VERSION 5.8 ;
BUSBITCHARS "[]" ;
DIVIDERCHAR "/" ;
UNITS
    DATABASE MICRONS 1000 ;
END UNITS

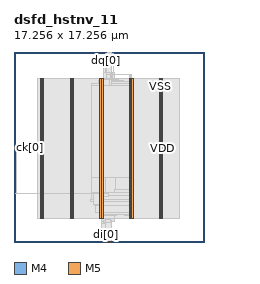
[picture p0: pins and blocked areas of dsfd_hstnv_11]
MACRO dsfd_hstnv_11
  FOREIGN dsfd_hstnv_11 0 0 ;
  CLASS BLOCK ;
  SIZE 17.256 BY 17.256 ;
  PIN ck[0]
    DIRECTION INPUT ;
    USE SIGNAL ;
    PORT
      LAYER M4 ;
        RECT  0 8.592 0.084 8.616 ;
    END
    PORT
      LAYER M4 ;
        RECT  0.06 8.592 0.227 8.616 ;
    END
  END ck[0]
  PIN di[0]
    DIRECTION INPUT ;
    USE SIGNAL ;
    PORT
      LAYER M5 ;
        RECT  8.352 0 8.376 0.084 ;
    END
  END di[0]
  PIN di[10]
    DIRECTION INPUT ;
    USE SIGNAL ;
    PORT
      LAYER M5 ;
        RECT  8.832 0 8.856 0.084 ;
    END
  END di[10]
  PIN di[1]
    DIRECTION INPUT ;
    USE SIGNAL ;
    PORT
      LAYER M5 ;
        RECT  8.4 0 8.424 0.084 ;
    END
  END di[1]
  PIN di[2]
    DIRECTION INPUT ;
    USE SIGNAL ;
    PORT
      LAYER M5 ;
        RECT  8.448 0 8.472 0.084 ;
    END
  END di[2]
  PIN di[3]
    DIRECTION INPUT ;
    USE SIGNAL ;
    PORT
      LAYER M5 ;
        RECT  8.496 0 8.52 0.084 ;
    END
  END di[3]
  PIN di[4]
    DIRECTION INPUT ;
    USE SIGNAL ;
    PORT
      LAYER M5 ;
        RECT  8.544 0 8.568 0.084 ;
    END
  END di[4]
  PIN di[5]
    DIRECTION INPUT ;
    USE SIGNAL ;
    PORT
      LAYER M5 ;
        RECT  8.592 0 8.616 0.084 ;
    END
  END di[5]
  PIN di[6]
    DIRECTION INPUT ;
    USE SIGNAL ;
    PORT
      LAYER M5 ;
        RECT  8.64 0 8.664 0.084 ;
    END
  END di[6]
  PIN di[7]
    DIRECTION INPUT ;
    USE SIGNAL ;
    PORT
      LAYER M5 ;
        RECT  8.688 0 8.712 0.084 ;
    END
  END di[7]
  PIN di[8]
    DIRECTION INPUT ;
    USE SIGNAL ;
    PORT
      LAYER M5 ;
        RECT  8.736 0 8.76 0.084 ;
    END
  END di[8]
  PIN di[9]
    DIRECTION INPUT ;
    USE SIGNAL ;
    PORT
      LAYER M5 ;
        RECT  8.784 0 8.808 0.084 ;
    END
  END di[9]
  PIN dq[0]
    DIRECTION OUTPUT ;
    USE SIGNAL ;
    PORT
      LAYER M5 ;
        RECT  8.352 17.172 8.376 17.256 ;
    END
  END dq[0]
  PIN dq[10]
    DIRECTION OUTPUT ;
    USE SIGNAL ;
    PORT
      LAYER M5 ;
        RECT  8.832 17.172 8.856 17.256 ;
    END
  END dq[10]
  PIN dq[1]
    DIRECTION OUTPUT ;
    USE SIGNAL ;
    PORT
      LAYER M5 ;
        RECT  8.4 17.172 8.424 17.256 ;
    END
  END dq[1]
  PIN dq[2]
    DIRECTION OUTPUT ;
    USE SIGNAL ;
    PORT
      LAYER M5 ;
        RECT  8.448 17.172 8.472 17.256 ;
    END
  END dq[2]
  PIN dq[3]
    DIRECTION OUTPUT ;
    USE SIGNAL ;
    PORT
      LAYER M5 ;
        RECT  8.496 17.172 8.52 17.256 ;
    END
  END dq[3]
  PIN dq[4]
    DIRECTION OUTPUT ;
    USE SIGNAL ;
    PORT
      LAYER M5 ;
        RECT  8.544 17.172 8.568 17.256 ;
    END
  END dq[4]
  PIN dq[5]
    DIRECTION OUTPUT ;
    USE SIGNAL ;
    PORT
      LAYER M5 ;
        RECT  8.592 17.172 8.616 17.256 ;
    END
  END dq[5]
  PIN dq[6]
    DIRECTION OUTPUT ;
    USE SIGNAL ;
    PORT
      LAYER M5 ;
        RECT  8.64 17.172 8.664 17.256 ;
    END
  END dq[6]
  PIN dq[7]
    DIRECTION OUTPUT ;
    USE SIGNAL ;
    PORT
      LAYER M5 ;
        RECT  8.688 17.172 8.712 17.256 ;
    END
  END dq[7]
  PIN dq[8]
    DIRECTION OUTPUT ;
    USE SIGNAL ;
    PORT
      LAYER M5 ;
        RECT  8.736 17.172 8.76 17.256 ;
    END
  END dq[8]
  PIN dq[9]
    DIRECTION OUTPUT ;
    USE SIGNAL ;
    PORT
      LAYER M5 ;
        RECT  8.784 17.172 8.808 17.256 ;
    END
  END dq[9]
  PIN VDD
    DIRECTION INOUT ;
    USE POWER ;
    PORT
      LAYER M5 ;
        RECT  13.392 2.151 13.512 14.873 ;
        RECT  10.692 2.151 10.812 14.873 ;
        RECT  7.992 2.151 8.112 14.873 ;
        RECT  5.292 2.151 5.412 14.873 ;
        RECT  2.592 2.151 2.712 14.873 ;
    END
  END VDD
  PIN VSS
    DIRECTION INOUT ;
    USE GROUND ;
    PORT
      LAYER M5 ;
        RECT  13.2 2.137 13.32 14.859 ;
        RECT  10.5 2.137 10.62 14.859 ;
        RECT  7.8 2.137 7.92 14.859 ;
        RECT  5.1 2.137 5.22 14.859 ;
        RECT  2.4 2.137 2.52 14.859 ;
    END
  END VSS
  # OT_OBS_CLOSED layer=M5 d_um=1.536 added=0
  OBS
    LAYER RVTN ;
     RECT  2.16 2.16 15.066 2.295 ;
     RECT  2.16 2.565 15.066 2.835 ;
     RECT  2.16 3.105 15.066 3.375 ;
     RECT  2.16 3.645 15.066 3.915 ;
     RECT  2.16 4.185 15.066 4.455 ;
     RECT  2.16 4.725 15.066 4.995 ;
     RECT  2.16 5.265 15.066 5.535 ;
     RECT  2.16 5.805 15.066 6.075 ;
     RECT  2.16 6.345 15.066 6.615 ;
     RECT  2.16 6.885 15.066 7.155 ;
     RECT  2.16 7.425 15.066 7.695 ;
     RECT  2.16 7.965 15.066 8.235 ;
     RECT  2.16 8.505 15.066 8.775 ;
     RECT  2.16 9.045 15.066 9.315 ;
     RECT  2.16 9.585 15.066 9.855 ;
     RECT  2.16 10.125 15.066 10.395 ;
     RECT  2.16 10.665 15.066 10.935 ;
     RECT  2.16 11.205 15.066 11.475 ;
     RECT  2.16 11.745 15.066 12.015 ;
     RECT  2.16 12.285 15.066 12.555 ;
     RECT  2.16 12.825 15.066 13.095 ;
     RECT  2.16 13.365 15.066 13.635 ;
     RECT  2.16 13.905 15.066 14.175 ;
     RECT  2.16 14.445 15.066 14.715 ;
    LAYER RVTP ;
     RECT  2.16 2.295 15.066 2.565 ;
     RECT  2.16 2.835 15.066 3.105 ;
     RECT  2.16 3.375 15.066 3.645 ;
     RECT  2.16 3.915 15.066 4.185 ;
     RECT  2.16 4.455 15.066 4.725 ;
     RECT  2.16 4.995 15.066 5.265 ;
     RECT  2.16 5.535 15.066 5.805 ;
     RECT  2.16 6.075 15.066 6.345 ;
     RECT  2.16 6.615 15.066 6.885 ;
     RECT  2.16 7.155 15.066 7.425 ;
     RECT  2.16 7.695 15.066 7.965 ;
     RECT  2.16 8.235 15.066 8.505 ;
     RECT  2.16 8.775 15.066 9.045 ;
     RECT  2.16 9.315 15.066 9.585 ;
     RECT  2.16 9.855 15.066 10.125 ;
     RECT  2.16 10.395 15.066 10.665 ;
     RECT  2.16 10.935 15.066 11.205 ;
     RECT  2.16 11.475 15.066 11.745 ;
     RECT  2.16 12.015 15.066 12.285 ;
     RECT  2.16 12.555 15.066 12.825 ;
     RECT  2.16 13.095 15.066 13.365 ;
     RECT  2.16 13.635 15.066 13.905 ;
     RECT  2.16 14.175 15.066 14.445 ;
     RECT  2.16 14.715 15.066 14.85 ;
    LAYER M1 ;
     RECT  2.16 2.151 15.066 14.859 ;
    LAYER M2 ;
     RECT  2.16 2.151 15.066 14.859 ;
    LAYER M3 ;
     RECT  7.992 0.571 8.01 1.099 ;
     RECT  7.992 1.099 8.55 1.147 ;
     RECT  7.992 1.147 8.658 1.723 ;
     RECT  7.992 1.723 8.874 1.867 ;
     RECT  7.992 1.867 9.126 2.143 ;
     RECT  7.815 2.143 9.126 2.371 ;
     RECT  10.515 2.143 10.605 2.371 ;
     RECT  2.415 2.143 2.505 2.413 ;
     RECT  5.115 2.143 5.205 2.413 ;
     RECT  10.08 2.371 10.605 2.413 ;
     RECT  13.215 2.143 13.305 2.413 ;
     RECT  7.74 2.371 9.342 2.461 ;
     RECT  10.08 2.413 10.797 2.461 ;
     RECT  7.74 2.461 10.797 2.641 ;
     RECT  7.416 2.641 10.797 3.307 ;
     RECT  7.272 3.307 10.797 3.721 ;
     RECT  6.948 3.721 10.797 3.839 ;
     RECT  7.02 3.839 10.797 4.523 ;
     RECT  9.108 4.523 10.797 4.793 ;
     RECT  7.02 4.523 8.334 5.881 ;
     RECT  9.216 4.793 10.797 5.881 ;
     RECT  7.02 5.881 10.797 14.251 ;
     RECT  7.02 14.251 10.854 14.369 ;
     RECT  2.415 2.413 2.697 14.597 ;
     RECT  5.115 2.413 5.397 14.597 ;
     RECT  7.632 14.369 10.797 14.597 ;
     RECT  13.215 2.413 13.497 14.597 ;
     RECT  7.632 14.597 9.918 14.639 ;
     RECT  7.704 14.639 9.45 14.711 ;
     RECT  8.007 14.711 9.45 14.747 ;
     RECT  8.007 14.747 9.342 14.783 ;
     RECT  2.607 14.597 2.697 14.867 ;
     RECT  5.307 14.597 5.397 14.867 ;
     RECT  8.007 14.783 9.126 14.867 ;
     RECT  10.656 14.597 10.797 14.867 ;
     RECT  13.407 14.597 13.497 14.867 ;
     RECT  10.656 14.867 10.674 15.245 ;
     RECT  8.136 14.867 9.126 15.389 ;
     RECT  8.136 15.389 8.298 16.589 ;
     RECT  8.136 16.589 8.154 16.637 ;
     RECT  9.036 15.389 9.054 17.117 ;
    LAYER M4 ;
     RECT  0.181 4.416 2.408 4.44 ;
     RECT  2.408 2.148 2.512 14.592 ;
     RECT  2.512 2.418 2.6 14.592 ;
     RECT  2.6 2.418 2.704 14.862 ;
     RECT  2.704 4.416 5.108 4.44 ;
     RECT  5.108 2.148 5.212 14.592 ;
     RECT  5.212 2.418 5.3 14.592 ;
     RECT  5.3 2.418 5.404 14.862 ;
     RECT  5.404 4.416 7.261 4.44 ;
     RECT  7.261 3.408 7.808 4.44 ;
     RECT  7.808 2.148 8 14.592 ;
     RECT  8 2.148 8.104 14.862 ;
     RECT  8.125 16.608 8.269 16.632 ;
     RECT  8.269 16.56 8.387 16.632 ;
     RECT  8.104 14.256 8.405 14.862 ;
     RECT  7.981 0.576 8.483 0.6 ;
     RECT  8.125 1.728 8.492 1.992 ;
     RECT  8.387 16.608 8.531 16.632 ;
     RECT  8.104 4.128 8.561 4.44 ;
     RECT  8.492 1.104 8.579 1.992 ;
     RECT  8.561 4.128 8.597 4.248 ;
     RECT  8.579 1.152 8.713 1.992 ;
     RECT  8.405 14.256 8.849 15.384 ;
     RECT  8.713 1.728 8.857 1.992 ;
     RECT  8.857 1.728 8.885 1.896 ;
     RECT  8.849 14.784 8.921 15.384 ;
     RECT  8.581 17.088 9.065 17.112 ;
     RECT  8.885 1.872 9.137 1.896 ;
     RECT  8.921 15.216 9.137 15.384 ;
     RECT  8.597 4.224 10.508 4.248 ;
     RECT  9.137 15.216 10.508 15.24 ;
     RECT  10.508 2.148 10.612 15.24 ;
     RECT  10.612 2.418 10.685 15.24 ;
     RECT  10.685 2.418 10.804 14.862 ;
     RECT  13.208 2.148 13.312 14.592 ;
     RECT  13.312 2.418 13.4 14.592 ;
     RECT  13.4 2.418 13.504 14.862 ;
    LAYER M5 ;
     RECT  8.352 0.016 8.856 1.763 ;
     RECT  8.352 1.763 8.808 2.003 ;
     RECT  2.4 2.137 2.52 2.151 ;
     RECT  5.1 2.137 5.22 2.151 ;
     RECT  10.5 2.137 10.62 2.151 ;
     RECT  13.2 2.137 13.32 2.151 ;
     RECT  0.192 4.405 0.216 8.627 ;
     RECT  7.8 2.137 8.112 14.245 ;
     RECT  7.8 14.245 8.664 14.773 ;
     RECT  2.4 2.151 2.712 14.859 ;
     RECT  5.1 2.151 5.412 14.859 ;
     RECT  7.8 14.773 8.76 14.859 ;
     RECT  10.5 2.151 10.812 14.859 ;
     RECT  13.2 2.151 13.512 14.859 ;
     RECT  2.592 14.859 2.712 14.873 ;
     RECT  5.292 14.859 5.412 14.873 ;
     RECT  7.992 14.859 8.76 14.873 ;
     RECT  10.692 14.859 10.812 14.873 ;
     RECT  13.392 14.859 13.512 14.873 ;
     RECT  8.4 14.873 8.76 15.205 ;
     RECT  8.4 15.205 8.808 15.349 ;
     RECT  8.4 15.349 8.856 16.549 ;
     RECT  8.352 16.549 8.856 17.232 ;
  END
END dsfd_hstnv_11
END LIBRARY
